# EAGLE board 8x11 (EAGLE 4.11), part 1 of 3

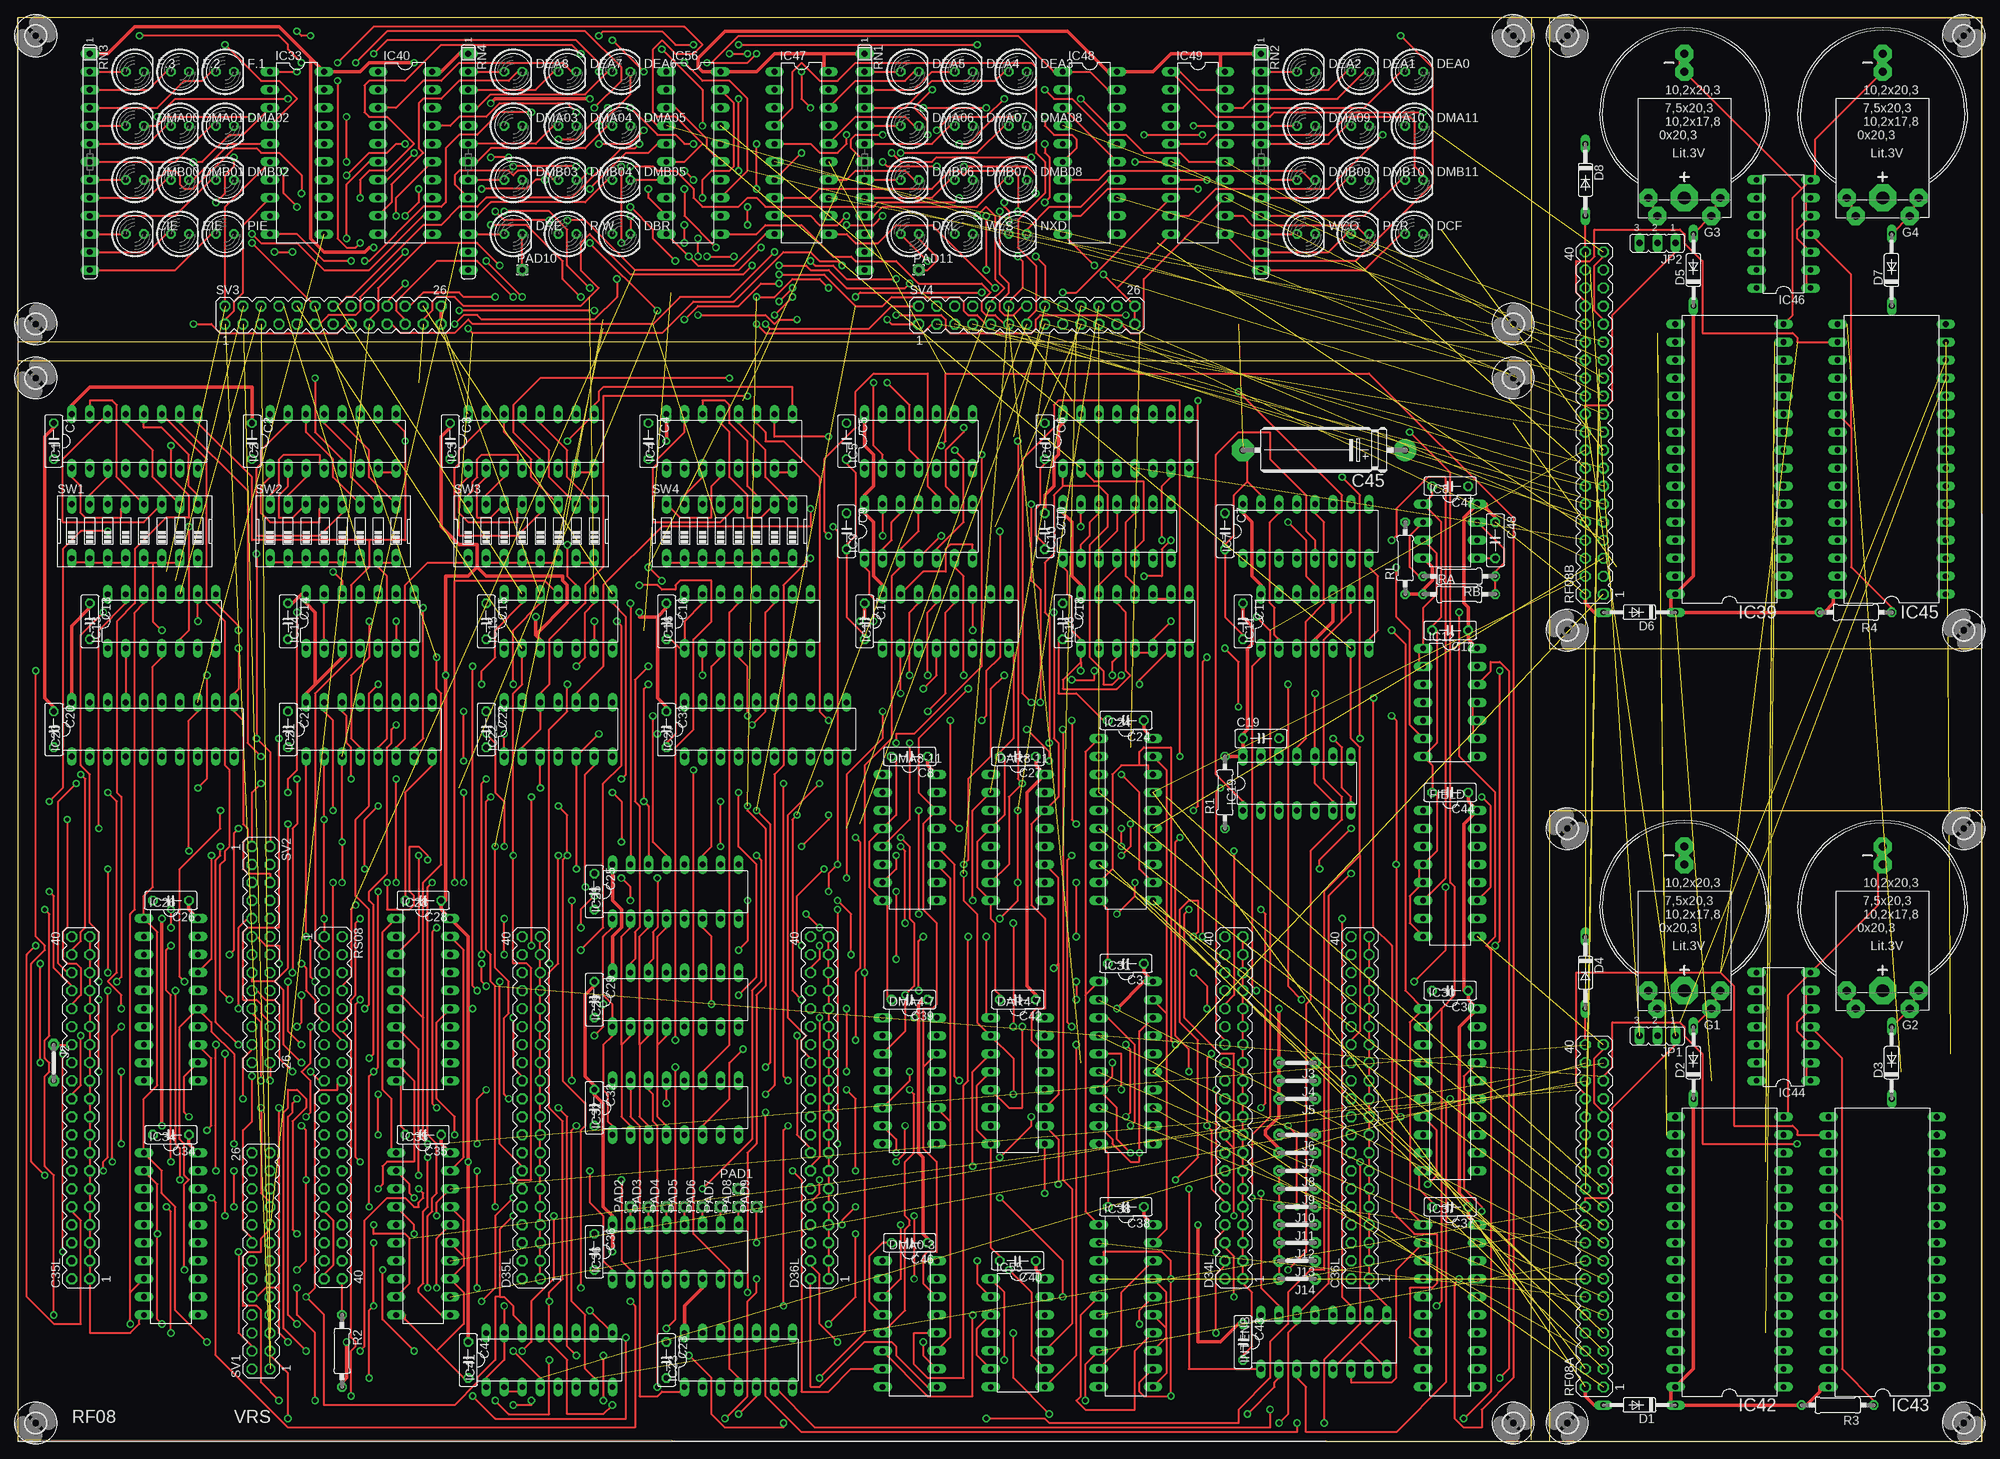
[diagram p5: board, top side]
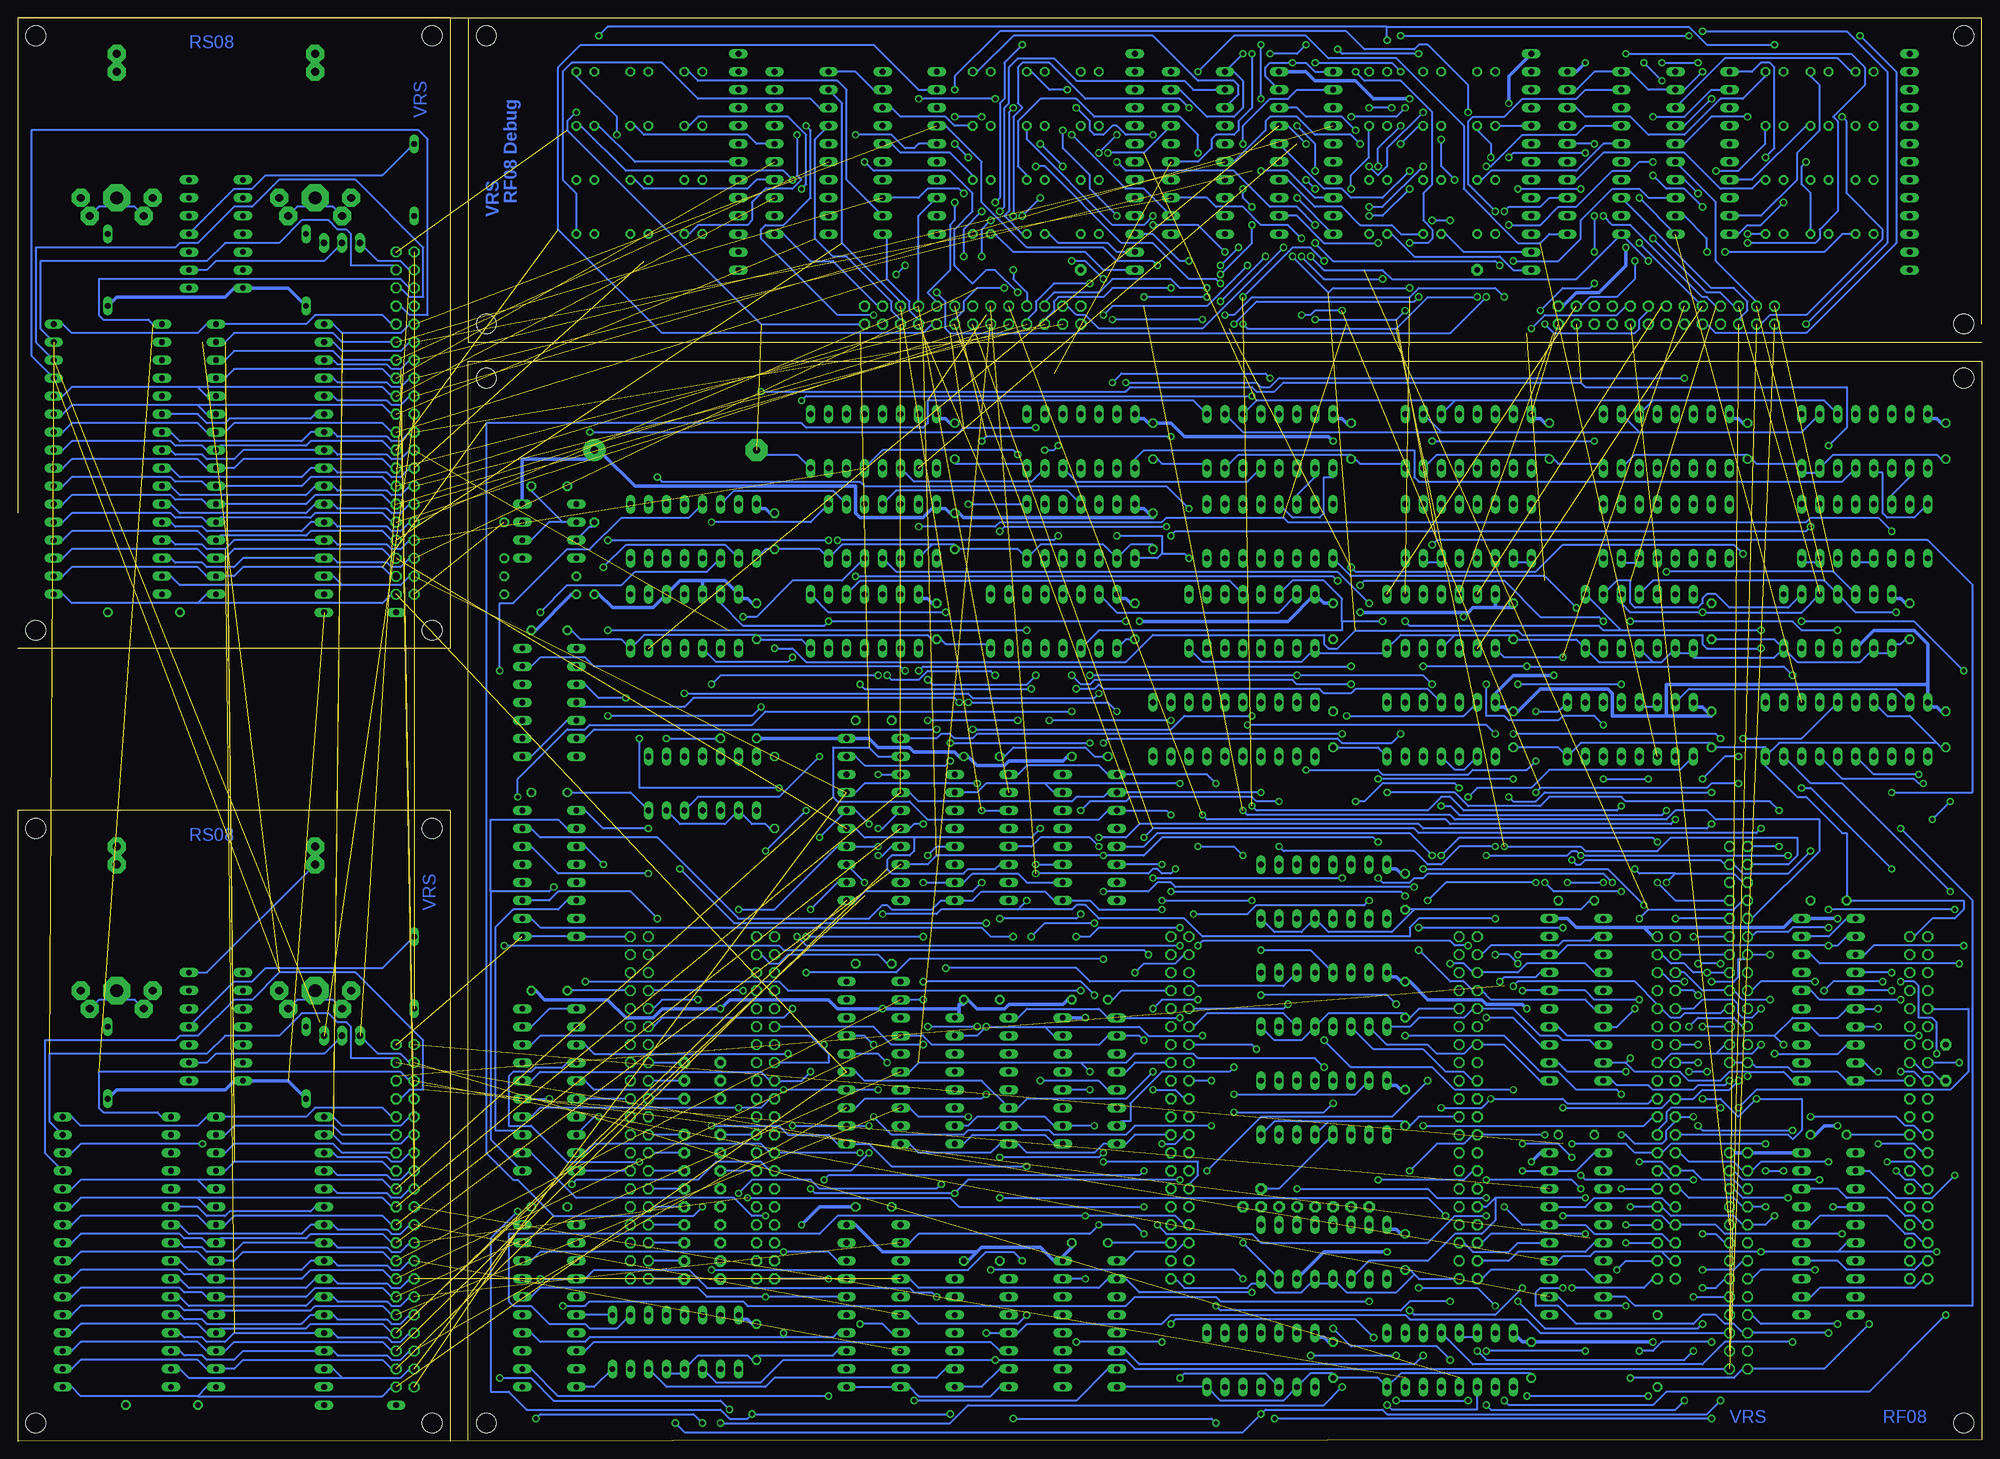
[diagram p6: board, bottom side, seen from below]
Size 276.86 x 200.67 mm. Coordinates in mm from the lower left corner, seen from the top.
Outline: 0.01,0.18 276.69,0 0.01,0.18
Outline: 213.34,0.18 213.34,152.25 0.01,152.25 0.01,0.18
Outline: 215.9,0.01 215.9,88.92 276.86,88.92 276.86,0.01
Outline: 276.86,111.78 215.9,111.78 215.9,200.67 276.86,200.67
Outline: 276.86,200.67 0,200.67
Outline: 276.86,200.67 276.86,130.82
Outline: 276.86,200.67 0,200.67
Outline: 0,154.95 213.36,154.95 213.36,200.67
Outline: 0,157.49 0,200.67
Copper layers (1*16): Top 0.035mm / dielectric 1.5mm / Bottom 0.035mm
Design rules "olimex10mil": minimum track width 10mil, minimum drill 24mil, track to track 10mil, track to pad 10mil, pad to pad 10mil, via to via 10mil, smd to smd 10mil, copper to edge 40mil, drill to drill 10mil, minimum pad ring 10mil, minimum via ring 8mil, stop-mask expansion 0mil, vias tented up to drill 0mil, thermal gap 10mil
Net classes: 1 Power: width 0.508 mm

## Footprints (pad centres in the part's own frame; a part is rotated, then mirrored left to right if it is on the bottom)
C050-025X075 = drill 0.813 octagon: 1 -2.54,0; 2 2.54,0
MA20-2 = drill 1.016 octagon: 1 -24.13,-1.27; 2 -24.13,1.27; 3 -21.59,-1.27; 4 -21.59,1.27; 5 -19.05,-1.27; 6 -19.05,1.27; 7 -16.51,-1.27; 8 -16.51,1.27; 9 -13.97,-1.27; 10 -13.97,1.27; 11 -11.43,-1.27; 12 -11.43,1.27; 13 -8.89,-1.27; 14 -8.89,1.27; 15 -6.35,-1.27; 16 -6.35,1.27; 17 -3.81,-1.27; 18 -3.81,1.27; 19 -1.27,-1.27; 20 -1.27,1.27; 21 1.27,-1.27; 22 1.27,1.27; 23 3.81,-1.27; 24 3.81,1.27; 25 6.35,-1.27; 26 6.35,1.27; 27 8.89,-1.27; 28 8.89,1.27; 29 11.43,-1.27; 30 11.43,1.27; 31 13.97,-1.27; 32 13.97,1.27; 33 16.51,-1.27; 34 16.51,1.27; 35 19.05,-1.27; 36 19.05,1.27; 37 21.59,-1.27; 38 21.59,1.27; 39 24.13,-1.27; 40 24.13,1.27
E22-6 = drill 1.016 pad 3.15 round: + -11.43,0 | drill 1.016 pad 3.15 octagon: - 11.43,0
LED5MM = drill 0.813 octagon: A -1.27,0; K 1.27,0
DO35-10 = drill 0.813 long: A 5.08,0; C -5.08,0
DIL16 = drill 0.813 long: 1 -8.89,-3.81; 2 -6.35,-3.81; 3 -3.81,-3.81; 4 -1.27,-3.81; 5 1.27,-3.81; 6 3.81,-3.81; 7 6.35,-3.81; 8 8.89,-3.81; 9 8.89,3.81; 10 6.35,3.81; 11 3.81,3.81; 12 1.27,3.81; 13 -1.27,3.81; 14 -3.81,3.81; 15 -6.35,3.81; 16 -8.89,3.81
B2430UNI = drill 1.118 pad 2.54 octagon: + 3.81,14.605; +@1 -3.81,14.605; +@2 -5.08,12.065; +@3 5.08,12.065; - 0,-5.715; -@1 0,-8.255 | drill 1.803 pad 3.81 octagon: +@4 0,12.065
DIL14 = drill 0.813 long: 1 -7.62,-3.81; 2 -5.08,-3.81; 3 -2.54,-3.81; 4 0,-3.81; 5 2.54,-3.81; 6 5.08,-3.81; 7 7.62,-3.81; 8 7.62,3.81; 9 5.08,3.81; 10 2.54,3.81; 11 0,3.81; 12 -2.54,3.81; 13 -5.08,3.81; 14 -7.62,3.81
DIL08 = drill 0.813 long: 1 -3.81,-3.81; 2 -1.27,-3.81; 3 1.27,-3.81; 4 3.81,-3.81; 5 3.81,3.81; 6 1.27,3.81; 7 -1.27,3.81; 8 -3.81,3.81
DIL20 = drill 0.813 long: 1 -11.43,-3.81; 2 -8.89,-3.81; 3 -6.35,-3.81; 4 -3.81,-3.81; 5 -1.27,-3.81; 6 1.27,-3.81; 7 3.81,-3.81; 8 6.35,-3.81; 9 8.89,-3.81; 10 11.43,-3.81; 11 11.43,3.81; 12 8.89,3.81; 13 6.35,3.81; 14 3.81,3.81; 15 1.27,3.81; 16 -1.27,3.81; 17 -3.81,3.81; 18 -6.35,3.81; 19 -8.89,3.81; 20 -11.43,3.81
DIL32 = drill 0.813 long: 1 -19.05,-7.62; 2 -16.51,-7.62; 3 -13.97,-7.62; 4 -11.43,-7.62; 5 -8.89,-7.62; 6 -6.35,-7.62; 7 -3.81,-7.62; 8 -1.27,-7.62; 9 1.27,-7.62; 10 3.81,-7.62; 11 6.35,-7.62; 12 8.89,-7.62; 13 11.43,-7.62; 14 13.97,-7.62; 15 16.51,-7.62; 16 19.05,-7.62; 17 19.05,7.62; 18 16.51,7.62; 19 13.97,7.62; 20 11.43,7.62; 21 8.89,7.62; 22 6.35,7.62; 23 3.81,7.62; 24 1.27,7.62; 25 -1.27,7.62; 26 -3.81,7.62; 27 -6.35,7.62; 28 -8.89,7.62; 29 -11.43,7.62; 30 -13.97,7.62; 31 -16.51,7.62; 32 -19.05,7.62
05 = drill 0.813 pad 1.6 octagon: 1 -2.54,0; 2 2.54,0
JP2 = drill 0.914 long: 1 -2.54,0; 2 0,0; 3 2.54,0
1,6/0,8 = drill 0.813 pad 1.6 octagon: 1 0,0
0207/10 = drill 0.813 octagon: 1 -5.08,0; 2 5.08,0
SIL13 = drill 0.813 long: 1 -15.24,0; 2 -12.7,0; 3 -10.16,0; 4 -7.62,0; 5 -5.08,0; 6 -2.54,0; 7 0,0; 8 2.54,0; 9 5.08,0; 10 7.62,0; 11 10.16,0; 12 12.7,0; 13 15.24,0
MA13-2 = drill 1.016 octagon: 1 -15.24,-1.27; 2 -15.24,1.27; 3 -12.7,-1.27; 4 -12.7,1.27; 5 -10.16,-1.27; 6 -10.16,1.27; 7 -7.62,-1.27; 8 -7.62,1.27; 9 -5.08,-1.27; 10 -5.08,1.27; 11 -2.54,-1.27; 12 -2.54,1.27; 13 0,-1.27; 14 0,1.27; 15 2.54,-1.27; 16 2.54,1.27; 17 5.08,-1.27; 18 5.08,1.27; 19 7.62,-1.27; 20 7.62,1.27; 21 10.16,-1.27; 22 10.16,1.27; 23 12.7,-1.27; 24 12.7,1.27; 25 15.24,-1.27; 26 15.24,1.27
EDG-08 = drill 0.813 long: 1 -8.89,-3.81; 2 -6.35,-3.81; 3 -3.81,-3.81; 4 -1.27,-3.81; 5 1.27,-3.81; 6 3.81,-3.81; 7 6.35,-3.81; 8 8.89,-3.81; 9 8.89,3.81; 10 6.35,3.81; 11 3.81,3.81; 12 1.27,3.81; 13 -1.27,3.81; 14 -3.81,3.81; 15 -6.35,3.81; 16 -8.89,3.81
2,8 = hole 2.8: 0,0

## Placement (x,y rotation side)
C1  0.1  [C050-025X075]  5.08,140.98 270 top
C2  0.1  [C050-025X075]  33.02,140.98 270 top
C3  0.1  [C050-025X075]  60.96,140.98 270 top
C4  0.1  [C050-025X075]  88.9,140.98 270 top
C5  0.1  [C050-025X075]  116.84,140.98 270 top
C6  0.1  [C050-025X075]  144.78,140.98 270 top
C7  0.1  [C050-025X075]  170.18,128.28 270 top
C8  0.1  [C050-025X075]  125.73,96.53 180 top
C9  0.1  [C050-025X075]  116.84,128.28 270 top
C10  0.1  [C050-025X075]  144.78,128.28 270 top
C11  0.1  [C050-025X075]  172.72,115.58 270 top
C12  0.1  [C050-025X075]  201.93,114.31 180 top
C13  0.1  [C050-025X075]  10.16,115.58 270 top
C14  0.1  [C050-025X075]  38.1,115.58 270 top
C15  0.1  [C050-025X075]  66.04,115.58 270 top
C16  0.1  [C050-025X075]  91.44,115.58 270 top
C17  0.1  [C050-025X075]  119.38,115.58 270 top
C18  0.1  [C050-025X075]  147.32,115.58 270 top
C19  0.1  [C050-025X075]  175.26,99.08 0 top
C20  0.1  [C050-025X075]  5.08,100.34 270 top
C21  0.1  [C050-025X075]  38.1,100.34 270 top
C22  0.1  [C050-025X075]  66.04,100.34 270 top
C23  0.1  [C050-025X075]  91.44,11.45 270 top
C24  0.1  [C050-025X075]  156.21,101.61 180 top
C25  0.1  [C050-025X075]  81.28,77.48 270 top
C26  0.1  [C050-025X075]  21.59,76.22 180 top
C27  0.1  [C050-025X075]  140.97,96.53 180 top
C28  0.1  [C050-025X075]  57.15,76.22 180 top
C29  0.1  [C050-025X075]  81.28,62.24 270 top
C30  0.1  [C050-025X075]  201.93,63.52 180 top
C31  0.1  [C050-025X075]  156.21,67.33 180 top
C32  0.1  [C050-025X075]  81.28,47.01 270 top
C33  0.1  [C050-025X075]  91.44,100.34 270 top
C34  0.1  [C050-025X075]  21.59,43.2 180 top
C35  0.1  [C050-025X075]  57.15,43.2 180 top
C35L  [MA20-2]  8.89,47.01 90 top
C36  0.1  [C050-025X075]  81.28,26.69 270 top
C36L  [MA20-2]  189.23,47.01 90 top
C37  0.1  [C050-025X075]  201.93,33.04 180 top
C38  0.1  [C050-025X075]  156.21,33.04 180 top
C39  0.1  [C050-025X075]  125.73,62.24 180 top
C40  0.1  [C050-025X075]  140.97,25.41 180 top
C41  0.1  [C050-025X075]  63.5,11.45 270 top
C42  0.1  [C050-025X075]  140.97,62.24 180 top
C43  0.1  [C050-025X075]  172.72,13.99 270 top
C44  0.1  [C050-025X075]  201.93,91.45 180 top
C45  100uf  [E22-6]  184.15,139.71 180 top
C46  0.1  [C050-025X075]  125.73,27.96 180 top
C47  0.1  [C050-025X075]  201.93,134.63 180 top
C48  0.1  [C050-025X075]  208.28,127.02 270 top
CIE  [LED5MM]  16.51,170.19 0 top
D1  1N4148  [DO35-10]  228.6,5.09 180 top
D2  1N4148  [DO35-10]  236.22,53.36 90 top
D3  1N4148  [DO35-10]  264.16,53.36 90 top
D4  1N4148  [DO35-10]  220.98,66.06 270 top
D5  1N4148  [DO35-10]  236.22,165.11 90 top
D6  1N4148  [DO35-10]  228.6,116.86 180 top
D7  1N4148  [DO35-10]  264.16,165.11 90 top
D8  1N4148  [DO35-10]  220.98,177.81 270 top
D34L  [MA20-2]  171.45,47.01 90 top
D35L  [MA20-2]  72.39,47.01 90 top
D36L  [MA20-2]  113.03,47.01 90 top
DAR4-7  74LS193N  [DIL16]  140.97,50.81 270 top
DAR8-11  74LS193N  [DIL16]  140.97,85.11 270 top
DBR  [LED5MM]  85.09,170.19 0 top
DCF  [LED5MM]  196.85,170.19 0 top
DEA0  [LED5MM]  196.85,193.05 0 top
DEA1  [LED5MM]  189.23,193.05 0 top
DEA2  [LED5MM]  181.61,193.05 0 top
DEA3  [LED5MM]  140.97,193.05 0 top
DEA4  [LED5MM]  133.35,193.05 0 top
DEA5  [LED5MM]  125.73,193.05 0 top
DEA6  [LED5MM]  85.09,193.05 0 top
DEA7  [LED5MM]  77.47,193.05 0 top
DEA8  [LED5MM]  69.85,193.05 0 top
DMA00  [LED5MM]  16.51,185.43 0 top
DMA0-3  74LS193N  [DIL16]  125.73,16.53 270 top
DMA01  [LED5MM]  22.86,185.43 0 top
DMA02  [LED5MM]  29.21,185.43 0 top
DMA03  [LED5MM]  69.85,185.43 0 top
DMA04  [LED5MM]  77.47,185.43 0 top
DMA4-7  74LS193N  [DIL16]  125.73,50.81 270 top
DMA05  [LED5MM]  85.09,185.43 0 top
DMA06  [LED5MM]  125.73,185.43 0 top
DMA07  [LED5MM]  133.35,185.43 0 top
DMA08  [LED5MM]  140.97,185.43 0 top
DMA8-11  74LS193N  [DIL16]  125.73,85.11 270 top
DMA09  [LED5MM]  181.61,185.43 0 top
DMA10  [LED5MM]  189.23,185.43 0 top
DMA11  [LED5MM]  196.85,185.43 0 top
DMB00  [LED5MM]  16.51,177.81 0 top
DMB01  [LED5MM]  22.86,177.81 0 top
DMB02  [LED5MM]  29.21,177.81 0 top
DMB03  [LED5MM]  69.85,177.81 0 top
DMB04  [LED5MM]  77.47,177.81 0 top
DMB05  [LED5MM]  85.09,177.81 0 top
DMB06  [LED5MM]  125.73,177.81 0 top
DMB07  [LED5MM]  133.35,177.81 0 top
DMB08  [LED5MM]  140.97,177.81 0 top
DMB09  [LED5MM]  181.61,177.81 0 top
DMB10  [LED5MM]  189.23,177.81 0 top
DMB11  [LED5MM]  196.85,177.81 0 top
DRE  [LED5MM]  69.85,170.19 0 top
DRL  [LED5MM]  125.73,170.19 0 top
EIE  [LED5MM]  22.86,170.19 0 top
F.1  [LED5MM]  29.21,193.05 0 top
F.2  [LED5MM]  22.86,193.05 0 top
F.3  [LED5MM]  16.51,193.05 0 top
FIELD  74LS193N  [DIL16]  201.93,80.03 270 top
G1  B2430UNI  [B2430UNI]  234.95,75.58 180 top
G2  B2430UNI  [B2430UNI]  262.89,75.58 180 top
G3  B2430UNI  [B2430UNI]  234.95,187.34 180 top
G4  B2430UNI  [B2430UNI]  262.89,187.34 180 top
IC1  74LS151N  [DIL16]  16.51,140.98 0 top
IC2  74LS151N  [DIL16]  44.45,140.98 0 top
IC3  74LS151N  [DIL16]  72.39,140.98 0 top
IC4  74LS151N  [DIL16]  100.33,140.98 0 top
IC5  74LS20N  [DIL14]  127,140.98 0 top
IC6  74LS139N  [DIL16]  156.21,140.98 0 top
IC7  74LS139N  [DIL16]  181.61,128.28 0 top
IC8  LM555N  [DIL08]  201.93,128.28 270 top
IC9  74S74N  [DIL14]  127,128.28 0 top
IC10  74S74N  [DIL14]  154.94,128.28 0 top
IC11  74S74N  [DIL14]  182.88,115.58 0 top
IC12  74LS00N  [DIL14]  201.93,104.16 270 top
IC13  74180N  [DIL14]  20.32,115.58 0 top
IC14  74180N  [DIL14]  48.26,115.58 0 top
IC15  74180N  [DIL14]  76.2,115.58 0 top
IC16  74LS139N  [DIL16]  102.87,115.58 0 top
IC17  74LS139N  [DIL16]  130.81,115.58 0 top
IC18  74LS00N  [DIL14]  157.48,115.58 0 top
IC19  7407N  [DIL14]  180.34,92.72 0 top
IC20  74S240N  [DIL20]  19.05,100.34 0 top
IC21  74LS139N  [DIL16]  49.53,100.34 0 top
IC22  7407N  [DIL14]  76.2,100.34 0 top
IC23  74S74N  [DIL14]  101.6,11.45 0 top
IC24  74S240N  [DIL20]  156.21,87.64 270 top
IC25  74S138N  [DIL16]  92.71,77.48 0 top
IC26  74S240N  [DIL20]  21.59,62.24 270 top
IC27  SPARE  [DIL20]  105.41,100.34 0 top
IC28  74LS244N  [DIL20]  57.15,62.24 270 top
IC29  74S138N  [DIL16]  92.71,62.24 0 top
IC30  74S240N  [DIL20]  201.93,49.55 270 top
IC31  74S240N  [DIL20]  156.21,53.36 270 top
IC32  74S138N  [DIL16]  92.71,47.01 0 top
IC33  74LS240N  [DIL20]  39.37,181.62 270 top
IC34  74S240N  [DIL20]  21.59,29.23 270 top
IC35  74LS244N  [DIL20]  57.15,29.23 270 top
IC36  74S138N  [DIL16]  92.71,26.69 0 top
IC37  74S240N  [DIL20]  201.93,19.07 270 top
IC38  74S240N  [DIL20]  156.21,19.07 270 top
IC39  628512  [DIL32]  241.3,138.44 90 top
IC40  74LS240N  [DIL20]  54.61,181.62 270 top
IC41  74LS139N  [DIL16]  74.93,11.45 0 top
IC42  628512  [DIL32]  241.3,26.69 90 top
IC43  628512  [DIL32]  262.89,26.69 90 top
IC44  4011N  [DIL14]  248.92,58.44 90 top
IC45  628512  [DIL32]  264.16,138.44 90 top
IC46  4011N  [DIL14]  248.92,170.19 90 top
IC47  74LS240N  [DIL20]  110.49,181.62 270 top
IC48  74LS240N  [DIL20]  151.13,181.62 270 top
IC49  74LS240N  [DIL20]  166.37,181.62 270 top
IC55  7438N  [DIL14]  140.97,15.26 270 top
IC56  74LS240N  [DIL20]  95.25,181.62 270 top
INTENB  74LS193N  [DIL16]  184.15,13.99 0 top
J2  J5MM  [05]  5.08,53.36 270 top
J3  J5MM  [05]  180.34,53.36 180 top
J4  J5MM  [05]  180.34,50.81 180 top
J5  J5MM  [05]  180.34,48.27 180 top
J6  J5MM  [05]  180.34,43.2 180 top
J7  J5MM  [05]  180.34,40.66 180 top
J8  J5MM  [05]  180.34,38.12 180 top
J9  J5MM  [05]  180.34,35.58 180 top
J10  J5MM  [05]  180.34,33.04 180 top
J11  J5MM  [05]  180.34,30.5 180 top
J12  J5MM  [05]  180.34,27.96 180 top
J13  J5MM  [05]  180.34,25.41 180 top
J14  J5MM  [05]  180.34,22.88 180 top
JP1  [JP2]  231.14,57.16 180 top
JP2  [JP2]  231.14,168.92 180 top
NXD  [LED5MM]  140.97,170.19 0 top
PAD1  [1,6/0,8]  101.6,35.58 90 top
PAD2  [1,6/0,8]  86.36,33.04 90 top
PAD3  [1,6/0,8]  88.9,33.04 90 top
PAD4  [1,6/0,8]  91.44,33.04 90 top
PAD5  [1,6/0,8]  93.98,33.04 90 top
PAD6  [1,6/0,8]  96.52,33.04 90 top
PAD7  [1,6/0,8]  99.06,33.04 90 top
PAD8  [1,6/0,8]  101.6,33.04 90 top
PAD9  [1,6/0,8]  104.14,33.04 90 top
PAD10  [1,6/0,8]  71.12,165.11 0 top
PAD11  [1,6/0,8]  127,165.11 0 top
PER  [LED5MM]  189.23,170.19 0 top
PIE  [LED5MM]  29.21,170.19 0 top
R1  4.7K  [0207/10]  170.18,91.45 90 top
R2  4.7K  [0207/10]  45.72,12.71 270 top
R3  10 Megohm  [0207/10]  256.54,5.09 180 top
R4  10 Megohm  [0207/10]  259.08,116.86 180 top
R/W  [LED5MM]  77.47,170.19 0 top
RA  470K  [0207/10]  203.2,119.39 0 top
RB  1.5K  [0207/10]  203.2,121.94 180 top
RF08A  [MA20-2]  222.25,31.77 90 top
RF08B  [MA20-2]  222.25,143.52 90 top
RL  1K  [0207/10]  195.58,124.47 90 top
RN1  330  [SIL13]  119.38,180.35 270 top
RN2  330  [SIL13]  175.26,180.35 270 top
RN3  330  [SIL13]  10.16,180.35 270 top
RN4  330  [SIL13]  63.5,180.35 270 top
RS08  [MA20-2]  44.45,47.01 270 top
SV1  [MA13-2]  34.29,25.41 90 top
SV2  [MA13-2]  34.29,68.59 270 top
SV3  [MA13-2]  44.45,158.76 0 top
SV4  [MA13-2]  142.24,158.76 0 top
SW1  [EDG-08]  16.51,128.28 0 top
SW2  [EDG-08]  44.45,128.28 0 top
SW3  [EDG-08]  72.39,128.28 0 top
SW4  [EDG-08]  100.33,128.28 0 top
U$1  [2,8]  2.54,149.88 0 top
U$2  [2,8]  210.82,149.88 0 top
U$3  [2,8]  2.54,2.56 0 top
U$4  [2,8]  210.82,2.56 0 top
U$5  [2,8]  274.32,2.56 90 top
U$6  [2,8]  218.44,2.56 90 top
U$7  [2,8]  218.44,86.38 90 top
U$8  [2,8]  274.32,86.38 90 top
U$9  [2,8]  274.32,198.13 90 top
U$10  [2,8]  274.32,114.31 90 top
U$11  [2,8]  218.44,114.31 90 top
U$12  [2,8]  218.44,198.13 90 top
U$13  [2,8]  2.54,157.49 0 top
U$14  [2,8]  2.54,198.13 0 top
U$16  [2,8]  210.82,157.49 0 top
U$17  [2,8]  210.82,198.13 0 top
U$18  [SIERRA-PROTO]  0,0.01 0 top
WCO  [LED5MM]  181.61,170.19 0 top
WLS  [LED5MM]  133.35,170.19 0 top

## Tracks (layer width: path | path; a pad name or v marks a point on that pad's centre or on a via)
3CYC\
  Top 0.254: J2.1 C35L.28
601\  (via drill 0.61)
  Top 0.254: IC23.1 93.34,7 90.81,7 90.17,6.36 87.63,6.36 87.63,44.47 86.36,45.73 IC32.15 | IC9.13 v121.92,127.65 | IC18.4 158.12,111.14 159.38,111.14 IC18.5 160.02,113.05 v162.56,115.58 | v120.65,115.58 120.65,118.76 120.02,119.39 120.02,122.57 119.38,123.2 IC9.1 | v105.41,48.91 106.68,50.18 106.68,94 107.95,95.27 107.95,120.67 v111.76,124.47
  Bottom 0.254: 115.57,125.11 116.2,124.47 IC9.1 | 115.57,125.11 115.57,127.65 v121.92,127.65 | IC11.13 177.8,118.12 174.62,114.95 163.19,114.95 v162.56,115.58 v120.65,115.58 | v105.41,48.91 88.27,48.91 IC32.15 | v111.76,124.47 112.39,125.11 115.57,125.11
602\  (via drill 0.61)
  Top 0.254: v88.9,109.23 87,107.33 87,90.19 87.63,89.55 87.63,72.41 87,71.77 87,67.96 86.36,67.33 IC29.15 | 149.86,109.87 v149.86,108.6 | 149.86,109.87 IC18.1 149.86,113.05 148.59,114.31 148.59,118.76 147.96,119.39 147.96,122.57 147.32,123.2 IC10.1 | 149.86,109.87 147.32,107.33 147.32,106.06 154.94,106.06 156.84,107.97 156.21,108.6 156.21,116.86 154.94,118.12 IC18.12
  Bottom 0.254: v88.9,109.23 149.22,109.23 v149.86,108.6
604\  (via drill 0.61)
  Top 0.254: IC18.2 IC18.13 152.4,120.67 154.94,123.2 IC10.4 | v86.36,118.12 IC25.15
  Bottom 0.254: v86.36,118.12 90.81,122.57 153.03,122.57 IC10.4
611\  (via drill 0.61)
  Top 0.254: v90.17,7.63 90.17,44.47 89.53,45.1 89.53,48.91 88.9,49.55 IC32.14 | v177.8,2.56 179.07,3.83 179.07,15.26 180.34,16.53 INTENB.14 184.78,22.24 184.78,76.85 v187.96,80.03
  Bottom 0.254: v90.17,7.63 92.71,5.09 142.88,5.09 145.41,2.56 v177.8,2.56 | v187.96,80.03 200.66,80.03 204.47,83.83 FIELD.14
612\  (via drill 0.61)
  Top 0.254: v90.17,79.39 90.17,72.41 89.53,71.77 89.53,67.96 88.9,67.33 IC29.14 | v116.84,79.39 116.84,94 121.92,99.08 v121.92,102.89 | v142.88,104.16 141.6,105.42 141.6,138.44 146.05,142.89 146.05,146.06 146.69,146.7 163.83,146.7 v163.83,96.53
  Bottom 0.254: v116.84,79.39 v90.17,79.39 | v121.92,102.89 123.19,104.16 v142.88,104.16 | v163.83,96.53 169.54,90.82 180.97,90.82 IC19.5
614\  (via drill 0.61)
  Top 0.254: v73.66,92.09 IC22.3 | IC25.14 88.9,89.55 v88.27,90.19 88.27,106.06 v88.9,106.7 | v128.27,107.97 128.27,116.86 129.54,118.12 IC17.13
  Bottom 0.254: v73.66,92.09 74.3,92.72 84.45,92.72 87,90.19 v88.27,90.19 | v128.27,107.97 127,106.7 125.73,106.7 125.09,107.33 97.16,107.33 96.52,106.7 v88.9,106.7
621\  (via drill 0.61)
  Top 0.254: v105.41,46.37 105.41,6.36 110.49,1.28 180.34,1.28 v180.34,2.56 | v203.84,3.19 207.65,7 207.65,69.23 207.01,69.86 208.28,71.14 208.28,91.45 203.2,96.53 v203.2,116.86 | v91.44,47.64 IC32.13
  Bottom 0.254: v91.44,47.64 92.71,46.37 v105.41,46.37 | v180.34,2.56 181.61,3.83 203.2,3.83 v203.84,3.19 | v203.2,116.86 199.39,120.67 191.77,120.67 189.87,122.57 179.71,122.57 IC7.3
622\  (via drill 0.61)
  Top 0.254: v101.6,69.23 102.87,70.5 v102.87,76.22 | v115.57,76.22 117.47,74.31 v117.47,68.59 | v208.28,69.86 208.91,70.5 v208.91,108.6
  Bottom 0.254: v101.6,69.23 94.61,69.23 IC29.13 | v115.57,76.22 v102.87,76.22 | v117.47,68.59 118.11,69.23 168.91,69.23 169.54,69.86 v208.28,69.86 | v208.91,108.6 208.91,118.12 207.01,118.12 199.39,125.75 196.22,125.75 191.77,130.19 182.25,130.19 IC7.13
624\  (via drill 0.61)
  Top 0.254: 89.53,99.71 v89.53,102.25 | 89.53,99.71 89.53,84.47 91.44,82.56 IC25.13 | 150.5,62.88 150.5,32.4 IC38.1 | 150.5,62.88 IC31.1 | 150.5,62.88 150.5,97.17 IC24.1 | 89.53,99.71 v90.17,99.71
  Bottom 0.254: v89.53,102.25 73.03,102.25 IC22.13 | v90.17,99.71 141.6,99.71 142.24,99.08 144.78,99.08 145.41,99.71 146.69,99.71 147.32,99.08 IC24.1
641\
  Top 0.254: IC32.11 96.52,52.09 100.33,55.9 100.33,116.86 101.6,118.12 IC16.13
642\  (via drill 0.61)
  Top 0.254: v146.05,66.69 146.69,67.33 | 146.69,67.33 146.69,79.39 DAR8-11.11 | 146.69,67.33 146.69,48.91 DAR4-7.11
  Bottom 0.254: v146.05,66.69 127.64,66.69 125.73,64.78 111.12,64.78 110.49,64.15 98.42,64.15 IC29.11
644\
  Top 0.254: IC25.11 96.52,82.56 97.79,83.83 97.79,109.23 99.06,110.5 IC16.3
645\  (via drill 0.61)
  Top 0.254: 161.93,60.34 161.93,29.86 IC38.19 | 161.93,60.34 IC31.19 | 161.93,60.34 161.93,94.63 IC24.19 | v102.87,102.25 102.87,109.23 101.6,110.5 IC16.4 | v142.24,100.34 145.41,97.17 v145.41,95.9
  Bottom 0.254: v102.87,102.25 112.39,102.25 114.3,100.34 v142.24,100.34 | v145.41,95.9 146.05,95.27 157.48,95.27 158.75,96.53 IC24.19
ACB00\  (via drill 0.61)
  Top 0.254: IC38.12 158.12,8.27 158.12,7 158.75,6.36 v162.56,6.36 v162.56,22.88 162.56,25.41 161.29,26.69 153.03,26.69 153.03,26.05 IC38.3
  Bottom 0.254: v162.56,6.36 200.66,6.36 204.47,10.18 IC37.12 | v162.56,22.88 D34L.2
ACB01\  (via drill 0.61)
  Top 0.254: IC38.5 149.86,17.8 149.86,6.36 149.22,5.73 150.5,4.46 157.48,4.46 157.48,12.71 IC38.14 | v168.91,15.26 168.91,23.51 170.18,24.78 D34L.4
  Bottom 0.254: 168.91,14.62 196.22,14.62 196.85,13.99 203.2,13.99 204.47,15.26 IC37.14 | 168.91,14.62 161.93,14.62 161.29,15.26 IC38.14 | 168.91,14.62 v168.91,15.26
ACB02\  (via drill 0.61)
  Top 0.254: v158.12,16.53 158.12,18.43 IC38.16 | v171.45,20.34 171.45,26.05 170.18,27.32 D34L.6
  Bottom 0.254: v158.12,16.53 154.94,16.53 153.67,15.26 IC38.7 | IC37.16 204.47,20.34 203.2,21.61 180.97,21.61 179.71,20.34 v171.45,20.34 IC38.16
ACB03\  (via drill 0.61)
  Top 0.254: IC38.9 155.57,13.35 155.57,20.97 IC38.18 | v168.91,26.69 168.91,28.59 170.18,29.86 D34L.8
  Bottom 0.254: IC37.18 204.47,25.41 203.2,26.69 v168.91,26.69 162.56,26.69 161.29,25.41 IC38.18
ACB04\  (via drill 0.61)
  Top 0.254: D34L.10 170.18,33.67 168.28,35.58 168.28,43.83 v167.64,44.47 167.64,53.99 v168.28,54.62 | v156.84,44.47 157.48,45.1 157.48,55.9 153.67,59.7 IC31.3
  Bottom 0.254: v167.64,44.47 IC31.12 v156.84,44.47 | v168.28,54.62 195.58,54.62 196.85,55.9 IC30.3
ACB05\  (via drill 0.61)
  Top 0.254: v155.57,49.55 155.57,54.62 IC31.5 | v168.91,49.55 168.91,37.48 170.18,36.21 D34L.12
  Bottom 0.254: v155.57,49.55 IC31.14 v168.91,49.55 195.58,49.55 196.85,50.81 IC30.5
ACB06\  (via drill 0.61)
  Top 0.254: v154.31,53.36 154.31,51.45 IC31.7 154.94,47.01 154.94,42.56 v156.84,40.66 | v198.75,36.21 200.03,37.48 200.03,43.83 IC30.7
  Bottom 0.254: v154.31,53.36 155.57,54.62 IC31.16 | v198.75,36.21 198.12,36.84 180.97,36.84 178.44,39.38 172.09,39.38 170.81,38.12 D34L.14 159.38,38.12 v156.84,40.66
ACB07\  (via drill 0.61)
  Top 0.254: IC31.9 154.31,42.56 154.31,41.92 156.84,39.38 158.12,39.38 v158.12,40.66 158.12,57.8 IC31.18
  Bottom 0.254: IC30.9 196.85,40.66 195.58,41.92 172.09,41.92 170.81,40.66 D34L.16 v158.12,40.66
ACB08\  (via drill 0.61)
  Top 0.254: v155.57,94 158.12,91.45 158.12,80.66 IC24.12 | v171.45,31.77 171.45,41.29 | 171.45,41.29 170.18,42.56 D34L.18 | v165.1,74.95 164.47,74.31 164.47,59.7 169.54,54.62 171.45,54.62 171.45,41.29
  Bottom 0.254: v155.57,94 IC24.3 | v171.45,31.77 173.35,31.77 175.9,34.3 198.12,34.3 204.47,40.66 IC30.12 | v165.1,74.95 161.29,78.75 IC24.12
ACB09\  (via drill 0.61)
  Top 0.254: v155.57,83.83 v155.57,86.38 | v175.26,74.95 175.9,74.31 175.9,47.64 v175.26,47.01
  Bottom 0.254: v155.57,86.38 154.94,86.38 IC24.5 | v155.57,83.83 IC24.14 161.29,83.83 170.18,74.95 v175.26,74.95 | IC30.14 204.47,45.73 203.2,47.01 v175.26,47.01 172.09,47.01 170.81,48.27 D34L.22
ACB10\  (via drill 0.61)
  Top 0.254: v155.57,82.56 156.84,83.83 v156.84,87.01 | v163.83,85.11 163.19,84.47 163.19,57.16 165.1,55.26 v165.1,52.09
  Bottom 0.254: v155.57,82.56 154.94,82.56 153.67,83.83 IC24.7 | v156.84,87.01 158.75,88.92 IC24.16 v163.83,85.11 | IC30.16 204.47,50.81 203.2,52.09 172.09,52.09 170.81,50.81 D34L.24 166.37,50.81 v165.1,52.09
ACB11\  (via drill 0.61)
  Top 0.254: 158.12,95.27 159.38,95.27 159.38,94.63 IC24.18 | 158.12,95.27 155.57,95.27 154.31,94 154.31,80.66 IC24.9 | 158.12,95.27 158.12,97.17 158.75,97.81 162.56,97.81 162.56,56.53 v163.19,55.9
  Bottom 0.254: 163.83,55.9 162.56,54.62 162.56,53.36 D34L.26 | 163.83,55.9 165.1,57.16 203.2,57.16 204.47,55.9 IC30.18 | v163.19,55.9 163.83,55.9
ACCLEAR\  (via drill 0.61)
  Top 0.254: IC22.2 71.12,97.81 73.66,100.34 IC22.12 73.66,105.42 74.93,106.7 74.93,113.05 80.01,118.12 80.01,120.67 82.55,123.2 82.55,147.33 v102.87,147.33 | v171.45,83.2 171.45,62.88 170.18,61.61 D34L.32 | v165.74,88.92 166.37,89.55 v166.37,146.7
  Bottom 0.254: IC22.4 74.3,94.63 73.03,94.63 IC22.2 | v165.74,88.92 v171.45,83.2 | v166.37,146.7 165.74,147.33 v102.87,147.33
BAC00
  Top 0.254: DMA0-3.9 128.27,7.63 123.83,12.08 123.83,13.35 123.19,13.99 119.38,13.99 113.03,7.63 111.76,7.63 D36L.2
BAC01  (via drill 0.61)
  Top 0.254: v127.64,13.99 127.64,12.08 DMA0-3.10 | v115.57,13.99 113.03,16.53 113.03,23.51 111.76,24.78 D36L.4
  Bottom 0.254: v115.57,13.99 v127.64,13.99
BAC02
  Bottom 0.254: DMA0-3.1 120.65,25.41 119.38,26.69 113.67,26.69 112.39,27.96 D36L.6
BAC03  (via drill 0.61)
  Top 0.254: v126.36,31.77 v126.36,22.88
  Bottom 0.254: v126.36,22.88 DMA0-3.15 | D36L.8 112.39,30.5 113.67,31.77 v126.36,31.77 161.29,31.77 163.83,29.23 207.65,29.23 207.65,19.7 207.01,19.07 204.47,19.07 201.93,16.53 196.85,16.53 196.22,15.89 192.41,15.89 INTENB.10
BAC04  (via drill 0.61)
  Top 0.254: v165.1,35.58 165.1,10.18 INTENB.1 | v144.78,34.94 DAR4-7.9 | v113.03,36.84 113.03,34.94 111.76,33.67 D36L.10
  Bottom 0.254: DMA4-7.9 130.81,41.92 132.08,43.2 142.24,43.2 143.51,41.92 DAR4-7.9 | v165.1,35.58 164.47,34.94 v144.78,34.94 142.88,36.84 v113.03,36.84
BAC05  (via drill 0.61)
  Top 0.254: v175.26,34.94 175.26,21.61 177.8,19.07 INTENB.15 | v146.69,36.21 146.69,42.56 DAR4-7.10 | v123.83,39.38 125.09,40.66 v125.09,44.47
  Bottom 0.254: DAR4-7.10 142.88,44.47 141.6,45.73 132.08,45.73 130.81,44.47 DMA4-7.10 v125.09,44.47 | v175.26,34.94 173.35,36.84 165.1,36.84 163.83,35.58 147.32,35.58 v146.69,36.21 | v123.83,39.38 110.49,39.38 110.49,37.48 111.76,36.21 D36L.12
BAC06  (via drill 0.61)
  Top 0.254: v136.53,71.14 136.53,60.34 DAR4-7.1 | v113.03,59.7 113.03,40.02 111.76,38.75 D36L.14
  Bottom 0.254: DAR4-7.1 135.89,59.7 134.62,60.98 124.46,60.98 123.19,59.7 DMA4-7.1 v113.03,59.7 | v136.53,71.14 139.7,71.14 140.97,72.41 203.2,72.41 204.47,73.67 FIELD.10
BAC07  (via drill 0.61)
  Top 0.254: v187.96,86.38 183.51,81.93 v183.51,80.66 | v140.34,73.04 v140.34,58.44 | v109.86,57.16 109.86,43.2 111.76,41.29 D36L.16
  Bottom 0.254: 132.08,58.44 130.81,57.16 DMA4-7.15 | 132.08,58.44 v140.34,58.44 141.6,57.16 DAR4-7.15 | v187.96,86.38 194.31,86.38 196.85,88.92 FIELD.1 | v183.51,80.66 175.9,73.04 v140.34,73.04 | v109.86,57.16 117.47,57.16 118.75,58.44 132.08,58.44
BAC08  (via drill 0.61)
  Top 0.254: v115.57,74.95 v115.57,41.92
  Bottom 0.254: FIELD.15 204.47,86.38 203.2,85.11 186.69,85.11 175.26,73.67 156.84,73.67 154.94,75.58 154.31,75.58 153.67,74.95 147.96,74.95 146.69,76.22 DAR8-11.9 142.24,76.22 140.97,77.48 132.08,77.48 130.81,76.22 DMA8-11.9 125.73,76.22 124.46,74.95 v115.57,74.95 | v115.57,41.92 113.67,41.92 112.39,43.2 D36L.18
BAC09  (via drill 0.61)
  Top 0.254: v116.84,49.55 118.11,48.27 v118.11,38.12 | v163.19,36.84 166.37,40.02 166.37,56.53 163.83,59.07 163.83,74.95 165.1,76.22 166.37,76.22 166.37,71.77 v165.74,71.14 | v149.22,71.14 v149.22,78.75
  Bottom 0.254: DMA8-11.10 134.62,78.75 135.89,80.03 142.24,80.03 143.51,78.75 DAR8-11.10 v149.22,78.75 | v116.84,49.55 113.67,49.55 112.39,48.27 D36L.22 | v118.11,38.12 118.75,37.48 162.56,37.48 v163.19,36.84 | v165.74,71.14 v149.22,71.14
BAC10  (via drill 0.61)
  Top 0.254: v108.58,50.81 107.95,51.45 v107.95,92.72
  Bottom 0.254: DAR8-11.1 135.89,94 134.62,95.27 124.46,95.27 123.19,94 DMA8-11.1 109.22,94 v107.95,92.72 | v108.58,50.81 D36L.24
BAC11  (via drill 0.61)
  Top 0.254: v113.03,92.72 108.58,88.28 108.58,59.7 111.12,57.16 110.49,56.53 110.49,55.26 111.76,53.99 D36L.26
  Bottom 0.254: 132.08,92.72 130.81,91.45 DMA8-11.15 | 132.08,92.72 140.34,92.72 141.6,91.45 DAR8-11.15 | v113.03,92.72 132.08,92.72
BADDAC\  (via drill 0.61)
  Top 0.254: v174.62,63.52 173.99,64.15 173.99,109.23 175.26,110.5 IC11.1
  Bottom 0.254: v174.62,63.52 C36L.34
BBREAK\  (via drill 0.61)
  Top 0.254: IC41.1 66.04,8.91 68.58,11.45 IC41.15 v68.58,19.07 | v125.73,98.44 125.73,87.64 DMA8-11.5 | v145.41,98.44 145.41,116.22 144.78,116.86 144.78,123.84 146.05,125.11 146.05,133.36 147.32,134.63 | 147.32,134.63 IC6.1 | v180.97,62.24 179.07,64.15 v179.07,106.7 | v155.57,107.97 154.31,106.7 153.03,106.7 153.03,108.6 151.13,110.5 151.13,126.38 153.67,128.92 153.67,133.36 152.4,134.63 147.32,134.63 | v79.38,21.61 79.38,43.83 80.01,44.47 80.01,47.64 76.83,50.81 76.83,81.93 v77.47,82.56 77.47,88.28 v76.2,89.55 | v44.45,88.92 44.45,101.61 43.18,102.89 IC21.15
  Bottom 0.254: IC20.19 12.06,106.06 41.27,106.06 IC21.15 | v145.41,98.44 v125.73,98.44 | v180.97,62.24 186.06,62.24 187.32,60.98 C36L.32 | v179.07,106.7 177.8,107.97 v155.57,107.97 | v68.58,19.07 71.12,21.61 v79.38,21.61 | v77.47,82.56 80.64,85.74 116.2,85.74 118.11,83.83 DMA8-11.5 | v44.45,88.92 45.09,88.28 73.66,88.28 74.93,89.55 v76.2,89.55
BINIT  (via drill 0.61)
  Top 0.254: IC9.11 127,128.28 124.46,125.75 IC9.3 124.46,123.2 123.19,121.94 123.19,99.08 119.38,95.27 v119.38,66.06 119.38,15.26 v113.03,8.91 | IC10.3 152.4,125.75 154.94,128.28 IC10.11
  Bottom 0.254: IC9.11 128.91,134 153.03,134 IC10.11 | v113.03,8.91 112.39,9.54 100.97,9.54 IC23.3 | v119.38,66.06 118.11,67.33 113.67,67.33 112.39,68.59 D36L.38
BIOP1  (via drill 0.61)
  Top 0.254: v102.23,55.26 100.33,53.36 100.33,48.27 96.52,44.47 IC32.6
  Bottom 0.254: v102.23,55.26 102.87,55.9 D36L.28
BIOP2
  Bottom 0.254: IC29.6 98.42,60.34 109.22,60.34 111.12,58.44 D36L.30
BIOP4  (via drill 0.61)
  Top 0.254: v97.79,61.61 97.79,71.14 96.52,72.41 IC25.6
  Bottom 0.254: v97.79,61.61 98.42,60.98 D36L.32
BMB00
  Bottom 0.254: IC35.8 54.61,22.88 55.88,24.14 69.22,24.14 70.48,22.88 D35L.2
BMB01
  Bottom 0.254: IC35.6 54.61,27.96 55.88,26.69 65.41,26.69 66.67,25.41 D35L.4
BMB02  (via drill 0.61)
  Top 0.254: v55.88,29.23 55.88,30.5 IC35.4
  Bottom 0.254: v55.88,29.23 69.22,29.23 70.48,27.96 D35L.6
BMB03  (via drill 0.61)
  Top 0.254: v55.88,34.3 55.24,34.94 55.24,36.21 IC35.2
  Bottom 0.254: v55.88,34.3 68.58,34.3 | 68.58,34.3 69.85,33.04 D35L.10 | 68.58,34.3 68.58,31.13 70.48,29.23 74.3,29.23 78.11,25.41 86.36,25.41 IC36.3
BMB04  (via drill 0.61)
  Top 0.254: v85.09,36.84 85.09,25.41 86.36,24.14 IC36.2 | v67.94,64.78 67.94,41.92 71.12,38.75 D35L.14
  Bottom 0.254: v85.09,36.84 73.03,36.84 71.75,38.12 D35L.14 | v67.94,64.78 67.31,65.42 62.87,65.42 62.23,66.06 IC28.17
BMB05  (via drill 0.61)
  Top 0.254: v80.64,38.12 80.64,33.67 82.55,31.77 82.55,25.41 83.82,24.14 IC36.1 | v61.59,43.2 61.59,45.73 59.05,48.27 59.05,59.07 IC28.15
  Bottom 0.254: v80.64,38.12 76.83,41.92 73.03,41.92 71.75,43.2 D35L.18 v61.59,43.2
BMB06  (via drill 0.61)
  Top 0.254: v69.85,59.7 69.85,52.72 71.12,51.45 D35L.24 | 87.63,55.9 87.63,45.73 88.9,44.47 IC32.3 | 87.63,55.9 88.9,57.16 IC29.3 | 87.63,55.9 87.63,71.14 88.9,72.41 IC25.3
  Bottom 0.254: v69.85,59.7 66.04,59.7 62.23,55.9 IC28.13 | D35L.24 71.75,50.81 73.03,52.09 75.56,52.09 78.74,55.26 85.72,55.26 IC29.3
BMB07
  Top 0.254: 85.09,55.9 85.09,45.73 86.36,44.47 IC32.2 | 85.09,55.9 86.36,57.16 IC29.2 | 85.09,55.9 85.09,71.14 86.36,72.41 IC25.2
  Bottom 0.254: IC28.11 62.23,50.81 67.31,55.9 D35L.28 71.75,55.9 73.03,54.62 76.83,54.62 78.11,55.9 83.82,55.9 IC29.2
BMB08
  Top 0.254: IC32.1 83.82,44.47 83.19,45.1 83.19,48.91 82.55,49.55 82.55,55.9 83.82,57.16 IC29.1 83.82,61.61 82.55,62.88 82.55,71.14 83.82,72.41 IC25.1
  Bottom 0.254: IC28.8 54.61,55.9 55.24,56.53 59.05,56.53 59.69,57.16 62.23,57.16 66.04,60.98 D35L.32 71.75,60.98 73.03,59.7 79.38,59.7 80.64,58.44 IC29.1
BMB09  (via drill 0.61)
  Top 0.254: v79.38,69.23 82.55,72.41 82.55,92.72 85.09,95.27 85.09,114.95 v84.45,115.58
  Bottom 0.254: IC28.6 54.61,60.98 55.88,62.24 69.22,62.24 70.48,63.52 D35L.34 71.75,63.52 73.03,64.78 74.93,64.78 v79.38,69.23 | 90.17,115.58 90.17,114.31 124.46,114.31 IC17.3 | 90.17,115.58 90.17,118.76 92.71,121.3 97.16,121.3 IC16.14 | v84.45,115.58 90.17,115.58
BMB10  (via drill 0.61)
  Top 0.254: v125.73,107.97 125.73,116.86 127,118.12 IC17.14 | v96.52,107.97 IC16.2 | v74.93,67.33 74.93,100.34 77.47,102.89 v77.47,106.7
  Bottom 0.254: IC28.4 54.61,66.06 55.88,67.33 64.14,67.33 65.41,66.06 D35L.36 71.75,66.06 73.03,67.33 v74.93,67.33 | v125.73,107.97 v96.52,107.97 78.74,107.97 v77.47,106.7
BMB11
  Bottom 0.254: IC28.2 54.61,71.14 55.24,70.5 59.05,70.5 59.69,69.86 69.22,69.86 70.48,68.59 D35L.38
BRK_RQ\  (via drill 0.61)  (1 unrouted)
  Top 0.254: 189.23,82.56 189.23,57.8 187.96,56.53 C36L.28 | 189.23,82.56 189.23,97.81 187.96,99.08 IC11.6 | v39.37,21.61 39.37,17.8 41.91,15.26 v41.91,5.73 | v69.85,5.09 72.39,5.09 v72.39,5.73 | v82.55,12.08 v82.55,5.73 | v94.61,12.08 97.79,8.91 97.79,3.83 99.69,1.92 107.95,1.92 v107.95,2.56 | v136.53,3.19 144.78,3.19 145.41,2.56 172.09,2.56 172.09,4.46 176.53,8.91 176.53,13.99 179.07,16.53 179.07,20.97 182.25,24.14 184.15,24.14 184.15,77.48 189.23,82.56 | v95.25,182.89 93.98,182.89 92.71,184.16 90.17,184.16 v86.36,187.97 | v83.19,187.97 78.74,183.53 v76.2,183.53 | v74.3,177.81 73.03,177.81 71.75,176.54 v65.41,176.54 | v56.52,176.54 56.52,174.64 v54.61,172.73 | v54.61,167.65 48.26,161.3 48.26,159.4 47.62,158.76 43.81,158.76 42.55,157.49 SV3.11
  Bottom 0.254: v39.37,21.61 37.47,21.61 36.2,22.88 SV1.11 | v41.91,5.73 43.18,4.46 69.22,4.46 v69.85,5.09 | v82.55,5.73 v72.39,5.73 | v94.61,12.08 v82.55,12.08 | v107.95,2.56 108.58,3.19 v136.53,3.19 | v95.25,182.89 97.79,185.43 IC56.17 | v83.19,187.97 v86.36,187.97 | v76.2,183.53 76.2,179.72 v74.3,177.81 | v65.41,176.54 v56.52,176.54 | v54.61,172.73 v54.61,167.65
BTS1  (via drill 0.61)
  Top 0.254: v167.64,110.5 167,109.87 v167,71.14 | v113.03,69.86 113.03,67.96 111.76,66.69 D36L.36
  Bottom 0.254: v167.64,110.5 168.28,109.87 178.44,109.87 IC11.3 | v167,71.14 165.74,69.86 v113.03,69.86
BUSY
  Top 0.254: IC11.2 177.8,113.05 177.16,113.68 177.16,117.49 176.53,118.12 176.53,129.55 177.8,130.82 IC7.14
  Bottom 0.254: IC10.9 161.93,134 175.9,134 IC7.14
BWC0\  (via drill 0.61)  (1 unrouted)
  Top 0.254: v34.29,47.01 34.29,34.94 35.56,33.67 SV1.19 | v149.86,189.24 153.67,185.43 IC48.17 | v139.06,189.24 136.53,186.7 131.44,186.7 v129.54,184.8 | v121.92,172.73 120.65,171.46 v116.84,171.46 | v106.68,167.65 100.33,161.3 93.34,161.3 89.53,157.49 64.14,157.49 63.5,158.13 61.59,156.22 53.98,156.22 52.7,157.49 SV3.19 | v12.7,128.28 8.89,128.28 6.35,125.75 6.35,92.09 v4.45,90.19 | v6.99,87.64 6.99,72.41 6.35,71.77 6.35,67.96 6.99,67.33 8.26,67.33 8.89,66.69 8.89,62.88 7.62,61.61 C35L.32 | v149.86,128.92 IC10.13
  Bottom 0.254: v34.29,47.01 31.75,49.55 4.45,49.55 1.91,52.09 1.91,60.98 C35L.32 | v139.06,189.24 v149.86,189.24 | v129.54,184.8 129.54,182.26 125.73,178.45 125.73,176.54 v121.92,172.73 | v116.84,171.46 110.49,171.46 v106.68,167.65 | v149.86,128.92 139.06,128.92 138.43,129.55 115.57,129.55 114.94,130.19 98.42,130.19 97.79,129.55 24.77,129.55 24.13,130.19 14.61,130.19 v12.7,128.28 | v4.45,90.19 v6.99,87.64
CIE  (via drill 0.61)  (1 unrouted)
  Top 0.254: v139.06,11.45 139.06,20.97 IC55.1 | v201.93,48.27 201.29,47.64 201.29,8.27 194.31,1.28 181.61,1.28 181.61,7.63 180.34,8.91 INTENB.3 | IC33.8 31.75,171.46 31.75,161.94 30.48,160.67 30.48,159.4 29.21,158.13 SV3.1
  Bottom 0.254: INTENB.3 178.44,8.27 172.09,8.27 168.91,11.45 v139.06,11.45 120.65,11.45 119.38,10.18 SV1.1 | IC30.15 v201.93,48.27
DA00\
  Bottom 0.254: J14.1 C36L.2
DA01\
  Bottom 0.254: J13.1 C36L.4
DA02\
  Bottom 0.254: J12.1 C36L.6
DA03\
  Bottom 0.254: J11.1 C36L.8
DA04\
  Bottom 0.254: J10.1 C36L.10
DA05\
  Bottom 0.254: J9.1 C36L.12
DA06\
  Bottom 0.254: J8.1 C36L.14
DA07\
  Bottom 0.254: J7.1 C36L.16
DA08\
  Bottom 0.254: J6.1 C36L.18
DA09\
  Bottom 0.254: J5.1 C36L.22
DA10\
  Bottom 0.254: J4.1 C36L.24
DA11\
  Bottom 0.254: J3.1 C36L.26
DAR04  (via drill 0.61)  (1 unrouted)
  Top 0.254: v156.21,45.73 156.84,46.37 156.84,55.26 v156.21,55.9 | IC41.2 69.22,7 70.48,7 IC41.3 | v45.72,78.75 v45.72,84.47 IC21.3 | v83.82,5.09 82.55,3.83 77.47,3.83 77.47,11.45 74.93,13.99 v74.93,19.7 74.93,20.97 76.83,22.88 76.83,45.1 74.93,47.01 74.93,66.06 76.2,67.33 v76.2,82.56 | v108.58,44.47 107.95,43.83 v107.95,19.07 | v110.49,193.05 110.49,189.24 v111.76,187.97 | v136.53,172.73 v136.53,165.11
  Bottom 0.254: v156.21,45.73 153.67,43.2 143.51,43.2 142.88,43.83 139.06,43.83 138.43,44.47 DAR4-7.7 135.89,44.47 135.25,43.83 131.44,43.83 130.81,43.2 120.65,43.2 119.38,44.47 v108.58,44.47 | v156.21,55.9 157.48,57.16 IC31.17 | v45.72,78.75 43.18,76.22 SV2.8 | v83.82,5.09 83.19,4.46 71.12,4.46 IC41.3 | v76.2,82.56 73.66,85.11 46.35,85.11 v45.72,84.47 | v107.95,19.07 107.31,18.43 81.92,18.43 80.64,19.7 v74.93,19.7 | v110.49,193.05 105.41,198.13 95.25,198.13 92.08,194.96 82.55,194.96 73.03,185.43 73.03,176.54 65.41,168.92 62.23,168.92 60.96,170.19 IC40.11 | v111.76,187.97 113.03,189.24 126.36,189.24 131.44,194.32 135.25,194.32 135.89,193.69 135.89,188.61 135.25,187.97 136.53,186.7 v136.53,172.73 | v136.53,165.11 136.53,163.84 134.62,161.94 SV4.8
DAR05  (via drill 0.61)  (3 unrouted)
  Top 0.254: IC21.2 v43.18,87.64 v43.18,73.67 RS08.1 | v116.84,60.98 v116.84,52.09 | v110.49,62.24 109.22,63.52 109.22,87.64 v109.86,88.28 | v78.74,187.34 77.47,188.61 67.94,188.61 66.04,186.7 62.23,186.7 60.96,185.43 IC40.17 | v86.36,179.72 89.53,179.72 90.17,179.08 92.71,179.08 95.25,176.54 95.25,175.27 96.52,174 101.6,174 102.87,175.27 104.14,175.27 105.41,174 120.65,174 121.28,174.64 132.08,174.64 v132.72,175.27 | v135.25,172.73 136.53,174 137.79,172.73 137.79,163.84 139.06,162.57 137.16,160.67 SV4.10
  Bottom 0.254: IC31.15 158.75,52.09 157.48,50.81 140.97,50.81 DAR4-7.6 135.89,47.01 134.62,48.27 120.65,48.27 v116.84,52.09 | SV2.10 v43.18,73.67 | v116.84,60.98 115.57,62.24 v110.49,62.24 | v109.86,88.28 109.22,87.64 75.56,87.64 74.93,87.01 43.81,87.01 v43.18,87.64 | v78.74,187.34 83.82,182.26 83.82,179.72 85.09,178.45 v86.36,179.72 | v132.72,175.27 v135.25,172.73 | 251.46,118.12 250.19,119.39 IC39.1 | 251.46,118.12 269.24,118.12 270.51,119.39 IC45.1 | 251.46,118.12 225.43,118.12 224.16,119.39 RF08B.1 | 251.46,6.36 250.19,7.63 IC42.1 | 251.46,6.36 267.97,6.36 269.24,7.63 IC43.1 | 251.46,6.36 225.43,6.36 224.16,7.63 RF08A.1
DAR06  (via drill 0.61)  (3 unrouted)
  Top 0.254: v140.34,48.91 140.34,53.99 DAR4-7.2 135.25,59.07 135.25,74.31 133.35,76.22 v133.35,80.03 | IC21.1 v40.64,71.14 41.27,70.5 41.27,65.42 v41.91,64.78 | v113.67,80.66 109.86,76.85 109.86,70.5 v110.49,69.86 | v72.39,90.82 v72.39,69.86 | v101.6,179.08 v101.6,189.24 | v101.6,196.86 v135.25,196.86 | v139.06,174.64 139.06,174 139.7,173.37 v139.7,172.1 | v140.97,167.02 141.6,166.38 141.6,162.57 139.7,160.67 SV4.12
  Bottom 0.254: v140.34,48.91 140.97,48.27 157.48,48.27 158.75,47.01 IC31.13 | v40.64,71.14 SV2.12 | v41.91,64.78 43.81,64.78 45.09,66.06 RS08.6 | v133.35,80.03 117.47,80.03 116.84,80.66 116.2,80.66 115.57,80.03 114.3,80.03 v113.67,80.66 | v110.49,69.86 109.86,70.5 74.93,70.5 74.3,69.86 v72.39,69.86 | v72.39,90.82 71.12,92.09 63.5,92.09 60.96,94.63 42.55,94.63 IC21.1 | v101.6,179.08 97.79,179.08 93.98,175.27 IC56.8 | v101.6,189.24 v101.6,196.86 | v135.25,196.86 137.79,194.32 137.79,189.24 138.43,188.61 138.43,175.27 v139.06,174.64 | v139.7,172.1 140.97,170.83 v140.97,167.02 | RF08A.6 221.62,12.71 222.88,11.45 224.16,11.45 224.79,12.08 231.78,12.08 232.41,12.71 IC42.30 245.11,12.71 246.38,11.45 250.19,11.45 250.82,12.08 253.37,12.08 254,12.71 IC43.30 | RF08B.6 221.62,124.47 222.88,123.2 224.16,123.2 224.79,123.84 231.78,123.84 232.41,124.47 IC39.30 245.11,124.47 246.38,123.2 250.19,123.2 250.82,123.84 254.63,123.84 255.27,124.47 IC45.30
DAR07  (via drill 0.61)  (3 unrouted)
  Top 0.254: v134.62,38.75 134.62,52.09 DAR4-7.3 | IC4.9 109.22,148.6 82.55,148.6 81.92,147.97 81.92,146.7 81.28,146.06 IC3.9 v77.47,140.98 | 49.53,127.02 54.61,127.02 v54.61,140.98 54.61,142.25 53.34,143.52 IC2.9 | 49.53,127.02 33.02,127.02 33.02,135.9 25.4,143.52 IC1.9 | 49.53,127.02 49.53,123.2 46.99,120.67 46.99,110.5 41.91,105.42 41.91,70.5 43.18,69.23 RS08.3 | v179.07,44.47 180.34,43.2 v180.34,33.04 | v138.43,173.37 138.43,164.48 139.7,163.21 139.7,161.94 138.43,160.67 138.43,159.4 139.06,158.76 140.34,158.76 141.6,160.03 SV4.14
  Bottom 0.254: v134.62,38.75 153.67,38.75 156.84,41.92 IC31.11 161.29,41.92 162.56,43.2 168.28,43.2 169.54,44.47 v179.07,44.47 | RS08.3 SV2.14 | v77.47,140.98 v54.61,140.98 | v180.34,33.04 181.61,31.77 201.29,31.77 206.38,36.84 207.01,36.84 210.82,40.66 210.82,143.52 166.37,143.52 165.74,142.89 149.22,142.89 148.59,143.52 148.59,146.7 111.12,146.7 IC4.9 | v138.43,173.37 137.79,174 137.79,187.97 137.16,188.61 137.16,193.69 135.89,194.96 130.81,194.96 127.64,191.78 112.39,191.78 111.12,190.51 IC47.2 | IC43.2 269.24,10.18 267.97,11.45 251.46,11.45 250.19,10.18 IC42.2 246.38,10.18 245.11,11.45 225.43,11.45 224.16,10.18 RF08A.3 | IC45.2 270.51,121.94 269.24,123.2 251.46,123.2 250.19,121.94 IC39.2 246.38,121.94 245.11,123.2 225.43,123.2 224.16,121.94 RF08B.3
DAR08  (via drill 0.61)  (3 unrouted)
  Top 0.254: DAR8-11.7 139.7,81.3 139.7,90.82 v141.6,92.72 140.97,93.36 v140.97,140.98 | v38.73,66.06 38.73,86.38 39.37,87.01 v39.37,93.36 | v34.29,96.53 32.38,98.44 32.38,134 22.86,143.52 IC1.10 | v114.3,141.62 106.68,141.62 IC4.10 | v140.97,173.37 140.97,178.45 140.34,179.08 133.99,179.08 133.35,178.45 132.72,179.08 131.44,179.08 128.91,176.54 113.03,176.54 111.76,175.27 IC47.8 | v143.51,167.02 144.78,165.75 SV4.16
  Bottom 0.254: v141.6,92.72 157.48,92.72 158.75,91.45 IC24.17 | SV2.16 v38.73,66.06 40.64,66.06 41.91,67.33 43.81,67.33 45.09,68.59 RS08.4 | 48.26,142.25 25.4,142.25 IC1.10 | 48.26,142.25 IC2.10 | 76.2,142.25 48.26,142.25 | 76.2,142.25 IC3.10 | 76.2,142.25 104.14,142.25 IC4.10 | v39.37,93.36 36.2,96.53 v34.29,96.53 | v140.97,140.98 140.34,141.62 v114.3,141.62 | v140.97,173.37 143.51,170.83 v143.51,167.02 | 231.14,8.91 232.41,10.18 IC42.31 | 231.14,8.91 222.88,8.91 221.62,10.18 RF08A.4 | 231.14,8.91 252.73,8.91 254,10.18 IC43.31 | 231.14,120.67 232.41,121.94 IC39.31 | 231.14,120.67 222.88,120.67 221.62,121.94 RF08B.4 | 231.14,120.67 254,120.67 255.27,121.94 IC45.31
DAR09  (via drill 0.61)  (3 unrouted)
  Top 0.254: v29.84,62.24 28.57,63.52 28.57,81.3 29.21,81.93 29.21,83.2 29.84,83.83 29.84,94.63 29.21,95.27 29.21,115.58 26.67,118.12 26.67,138.44 IC1.11 | v132.72,86.38 131.44,87.64 v131.44,101.61 | v114.3,101.61 113.03,102.89 113.03,135.9 107.95,140.98 105.41,140.98 105.41,142.25 104.14,143.52 IC4.11 | v123.19,181.62 124.46,180.35 128.91,180.35 129.54,180.99 v142.88,180.99 | v144.78,182.89 144.78,181.62 145.41,180.99 145.41,175.27 v144.78,174.64
  Bottom 0.254: 150.5,85.11 150.5,83.2 151.13,82.56 153.67,82.56 154.31,81.93 154.31,80.66 153.67,80.03 143.51,80.03 142.88,80.66 139.06,80.66 138.43,81.3 DAR8-11.6 | 150.5,85.11 157.48,85.11 158.75,86.38 IC24.15 | RS08.5 41.91,66.06 39.37,63.52 SV2.18 34.92,63.52 33.66,62.24 v29.84,62.24 | 46.35,146.7 22.23,146.7 IC1.11 | 46.35,146.7 IC2.11 | 46.35,146.7 74.3,146.7 | 74.3,146.7 IC3.11 | 74.3,146.7 102.23,146.7 IC4.11 | 150.5,85.11 133.99,85.11 v132.72,86.38 | v114.3,101.61 v131.44,101.61 | v123.19,181.62 118.11,181.62 IC47.17 | v142.88,180.99 v144.78,182.89 | v144.78,174.64 144.78,172.1 145.41,171.46 145.41,165.11 148.59,161.94 147.32,160.67 SV4.18 | IC45.3 270.51,124.47 269.24,125.75 251.46,125.75 250.19,124.47 IC39.3 247.65,124.47 246.38,125.75 225.43,125.75 224.16,124.47 RF08B.5 | IC43.3 269.24,12.71 267.97,13.99 251.46,13.99 250.19,12.71 IC42.3 247.65,12.71 246.38,13.99 225.43,13.99 224.16,12.71 RF08A.5
DAR10  (via drill 0.61)  (3 unrouted)
  Top 0.254: v134.62,76.22 134.62,88.92 DAR8-11.2 | v154.94,74.31 157.48,76.85 v157.48,78.75 | v66.04,64.15 65.41,64.78 v65.41,67.33 | v68.58,68.59 v68.58,73.67
  Bottom 0.254: SV2.20 36.2,60.98 36.83,60.34 41.91,60.34 42.55,59.7 43.81,59.7 45.09,60.98 RS08.10 45.72,61.61 48.9,64.78 65.41,64.78 v66.04,64.15 | 135.89,74.95 v134.62,76.22 | 135.89,74.95 146.69,74.95 147.32,74.31 v154.94,74.31 | v157.48,78.75 IC24.13 | v65.41,67.33 66.67,68.59 v68.58,68.59 | v68.58,73.67 79.38,73.67 80.64,72.41 80.64,71.14 109.86,71.14 112.39,73.67 124.46,73.67 126.36,75.58 127.64,75.58 128.27,74.95 135.89,74.95 | IC48.8 149.86,172.73 SV4.20 | RF08A.10 221.62,17.8 222.88,16.53 224.16,16.53 224.79,17.16 231.78,17.16 232.41,17.8 IC42.28 235.59,17.8 236.85,16.53 250.19,16.53 250.82,17.16 253.37,17.16 254,17.8 IC43.28 | RF08B.10 221.62,129.55 222.88,128.28 224.16,128.28 224.79,128.92 231.78,128.92 232.41,129.55 IC39.28 235.59,129.55 236.85,128.28 250.19,128.28 250.82,128.92 254.63,128.92 255.27,129.55 IC45.28
DAR11  (via drill 0.61)  (3 unrouted)
  Top 0.254: v39.37,58.44 40.01,59.07 v40.01,62.88 | v140.97,88.92 v140.97,78.75 140.97,76.22 v138.43,73.67 | v36.83,99.08 36.83,72.41 32.38,72.41 31.75,71.77 31.75,62.24 33.66,62.24 34.29,61.61 34.29,60.34 35.56,59.07 SV2.22 | v66.04,99.71 67.31,98.44 67.31,91.45 68.58,90.19 v68.58,83.83 | v99.06,83.83 v99.06,90.19 | v127,88.92 v127,74.31
  Bottom 0.254: v40.01,62.88 40.64,63.52 RS08.7 | SV2.22 v39.37,58.44 | v140.97,78.75 142.24,77.48 157.48,77.48 158.75,76.22 IC24.11 | v140.97,88.92 DAR8-11.3 | v36.83,99.08 37.47,99.71 v66.04,99.71 | v68.58,83.83 73.66,83.83 76.2,81.3 78.11,81.3 80.01,83.2 98.42,83.2 v99.06,83.83 | v99.06,90.19 102.23,90.19 102.87,90.82 120.02,90.82 120.65,90.19 125.73,90.19 v127,88.92 | v127,74.31 127.64,73.67 v138.43,73.67 | IC49.2 160.66,188.61 160.66,168.92 152.4,160.67 SV4.22 | IC45.4 270.51,127.02 269.24,128.28 251.46,128.28 250.19,127.02 IC39.4 248.28,127.65 236.22,127.65 235.59,128.28 225.43,128.28 224.16,127.02 RF08B.7 | IC43.4 269.24,15.26 267.97,16.53 251.46,16.53 250.19,15.26 IC42.4 248.28,15.89 236.22,15.89 235.59,16.53 225.43,16.53 224.16,15.26 RF08A.7
DATA00\
  Bottom 0.254: IC34.12 24.13,20.34 22.86,21.61 9.53,21.61 8.26,22.88 C35L.2
DATA01\
  Bottom 0.254: IC34.14 20.32,25.41 19.05,24.14 9.53,24.14 8.26,25.41 C35L.4
DATA02\
  Bottom 0.254: IC34.16 24.13,30.5 22.86,31.77 13.34,31.77 10.79,29.23 9.53,29.23 8.26,27.96 C35L.6
DATA03\
  Bottom 0.254: IC34.18 20.32,35.58 19.05,34.3 13.34,34.3 10.79,31.77 9.53,31.77 8.26,30.5 C35L.8
DATA04\  (via drill 0.61)
  Top 0.254: v2.54,69.86 1.27,68.59 1.27,20.34 5.08,16.53 8.89,16.53 8.89,31.13 7.62,32.4 C35L.10
  Bottom 0.254: v2.54,69.86 15.24,69.86 16.51,68.59 IC26.3
DATA05\  (via drill 0.61)
  Top 0.254: v12.7,63.52 12.7,40.02 12.06,39.38 v12.06,38.12
  Bottom 0.254: v12.06,38.12 10.79,36.84 9.53,36.84 8.26,35.58 C35L.12 | v12.7,63.52 IC26.5
DATA06\  (via drill 0.61)
  Top 0.254: v14.61,58.44 13.34,57.16 v13.34,39.38
  Bottom 0.254: v13.34,39.38 9.53,39.38 8.26,38.12 C35L.14 | v14.61,58.44 IC26.7
DATA07\  (via drill 0.61)
  Top 0.254: v14.61,41.92 v14.61,52.09
  Bottom 0.254: v14.61,52.09 15.24,52.09 16.51,53.36 IC26.9 | v14.61,41.92 9.53,41.92 8.26,40.66 C35L.16
DATA08\  (via drill 0.61)
  Top 0.254: v24.13,45.73 23.5,46.37 23.5,51.45 IC26.12
  Bottom 0.254: v24.13,45.73 12.06,45.73 10.79,44.47 9.53,44.47 8.26,43.2 C35L.18
DATA09\  (via drill 0.61)
  Top 0.254: v8.89,57.16 8.89,50.18 7.62,48.91 C35L.22
  Bottom 0.254: v8.89,57.16 22.86,57.16 24.13,58.44 IC26.14
DATA10\  (via drill 0.61)
  Top 0.254: v11.43,52.09 v11.43,62.24
  Bottom 0.254: v11.43,62.24 22.86,62.24 24.13,63.52 IC26.16 | v11.43,52.09 9.53,52.09 8.26,50.81 C35L.24
DATA11\  (via drill 0.61)
  Top 0.254: v3.17,53.36 v3.17,67.33
  Bottom 0.254: v3.17,67.33 22.86,67.33 24.13,68.59 IC26.18 | v3.17,53.36 C35L.26
DATA_IN  (via drill 0.61)
  Top 0.254: v80.01,78.12 80.01,94 81.28,95.27 IC22.6 | v123.83,77.48 v123.83,67.96 | v165.74,66.06 167.64,64.15 v167.64,60.98
  Bottom 0.254: v80.01,78.12 113.67,78.12 114.3,78.75 116.2,78.75 117.47,77.48 v123.83,77.48 | v123.83,67.96 151.13,67.96 153.03,66.06 v165.74,66.06 | v167.64,60.98 168.91,59.7 186.06,59.7 187.32,58.44 C36L.30
DCXA\
  Top 0.254: IC18.9 161.93,118.76 160.66,118.76 IC18.10
  Bottom 0.254: IC16.12 106.05,121.3 158.12,121.3 IC18.10
DIMA\  (via drill 0.61)
  Top 0.254: IC37.1 196.22,32.4 196.22,59.07 IC30.1 195.58,63.52 195.58,112.41 v193.68,114.31 | IC17.11 v134.62,114.31
  Bottom 0.254: v134.62,114.31 v193.68,114.31 | IC30.19 204.47,58.44 201.93,60.98 IC30.1
DIML\  (via drill 0.61)
  Top 0.254: v186.69,73.67 186.69,20.34 187.96,19.07 INTENB.11 | v128.27,102.89 130.81,105.42 130.81,116.86 132.08,118.12 IC17.12 | v206.38,90.82 207.65,89.55 207.65,78.12 FIELD.11
  Bottom 0.254: v186.69,73.67 190.5,77.48 200.66,77.48 201.93,76.22 FIELD.11 | v128.27,102.89 171.45,102.89 173.35,100.98 196.22,100.98 196.85,100.34 199.39,100.34 206.38,93.36 v206.38,90.82
DIO00  (via drill 0.61)  (3 unrouted)
  Top 0.254: v44.45,122.57 45.72,121.3 IC14.12 | v50.16,27.96 v50.16,19.07 49.53,18.43 v49.53,8.91 | v15.88,16.53 15.88,20.97 | 15.88,20.97 IC34.8 | 15.88,20.97 15.88,74.31 16.51,74.95 16.51,116.86 17.78,118.12 IC13.12 | IC33.6 29.21,174 SV3.2
  Bottom 0.254: v44.45,122.57 20.95,122.57 IC13.12 | v50.16,19.07 58.42,19.07 59.69,20.34 IC35.12 | v50.16,27.96 RS08.36 | v15.88,16.53 22.23,10.18 SV1.2 33.66,10.18 34.92,8.91 v49.53,8.91 | IC43.17 256.54,45.73 257.18,46.37 264.8,46.37 265.43,47.01 265.43,52.09 222.88,52.09 221.62,50.81 RF08A.36 | IC45.17 257.81,157.49 258.44,158.13 264.8,158.13 265.43,158.76 265.43,163.84 222.88,163.84 221.62,162.57 RF08B.36
DIO01  (via drill 0.61)  (3 unrouted)
  Top 0.254: v31.11,26.69 31.11,15.26 33.02,13.35 SV1.4 | v12.06,116.86 8.89,113.68 8.89,95.27 10.16,94 10.16,73.04 11.43,71.77 v11.43,64.78 | v6.35,26.69 v6.35,54.62
  Bottom 0.254: IC14.11 46.35,121.3 22.23,121.3 IC13.11 17.78,116.86 v12.06,116.86 | 45.09,26.69 54.61,26.69 55.24,26.05 59.05,26.05 59.69,25.41 IC35.14 | 45.09,26.69 43.81,25.41 RS08.37 | 20.32,26.69 19.05,27.96 IC34.6 | 45.09,26.69 v31.11,26.69 20.32,26.69 | v11.43,64.78 9.53,64.78 8.89,64.15 8.89,59.7 6.99,59.7 6.35,59.07 v6.35,54.62 | v6.35,26.69 20.32,26.69 | IC33.15 37.47,174.64 37.47,166.38 31.75,160.67 SV3.4 | IC43.15 272.42,45.1 272.42,54.62 250.19,54.62 247.65,57.16 240.03,57.16 236.85,60.34 233.04,60.34 231.78,59.07 230.5,59.07 229.87,58.44 229.87,53.99 223.52,53.99 RF08A.37 | IC45.15 273.69,156.86 273.69,166.38 250.19,166.38 247.65,168.92 240.03,168.92 236.85,172.1 233.04,172.1 231.78,170.83 230.5,170.83 229.87,170.19 229.87,165.75 223.52,165.75 RF08B.37
DIO02  (via drill 0.61)  (3 unrouted)
  Top 0.254: v20.95,33.04 21.59,32.4 v21.59,15.26 | v59.05,21.61 59.05,28.59 IC35.16 | v39.37,116.86 39.37,94.63 38.1,93.36 v38.1,91.45 | v66.67,90.82 66.04,90.19 66.04,69.23 66.67,68.59 66.67,64.78 67.31,64.15 v67.31,33.04 | v46.35,169.56 46.35,177.18 49.53,180.35 IC40.6 | v250.82,41.92 237.49,41.92 237.49,54.62 234.95,57.16 234.95,58.44 234.31,59.07 224.79,59.07 224.79,52.72 223.52,51.45 RF08A.35
  Bottom 0.254: IC13.10 25.4,116.86 v39.37,116.86 49.53,116.86 50.8,118.12 IC14.10 | RS08.35 43.81,27.96 45.09,29.23 54.61,29.23 55.88,30.5 IC35.16 64.77,30.5 v67.31,33.04 | v20.95,33.04 IC34.4 | v21.59,15.26 SV1.6 33.66,15.26 34.92,16.53 36.2,16.53 37.47,17.8 39.37,17.8 40.64,16.53 57.15,16.53 59.69,19.07 62.87,19.07 62.87,20.97 62.23,21.61 v59.05,21.61 | v38.1,91.45 61.59,91.45 62.87,90.19 66.04,90.19 v66.67,90.82 | v46.35,169.56 38.73,161.94 36.83,161.94 34.92,160.03 SV3.6 | v250.82,41.92 267.97,41.92 269.24,40.66 IC43.14 | IC45.14 274.32,154.95 274.32,168.29 254.63,168.29 254,168.92 251.46,168.92 246.38,174 243.84,174 240.03,177.81 229.24,177.81 219.71,168.29 219.71,161.3 221.62,161.3 222.88,162.57 RF08B.35
DIO03  (via drill 0.61)  (3 unrouted)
